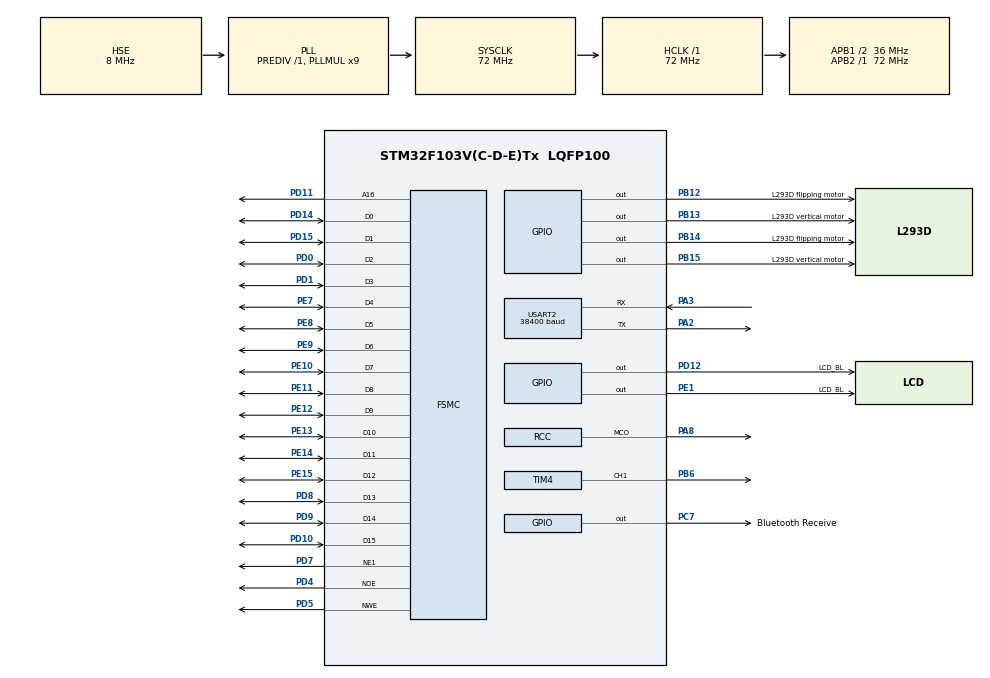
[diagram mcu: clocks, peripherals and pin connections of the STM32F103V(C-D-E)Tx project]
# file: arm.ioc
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Mcu.Family=STM32F1
Mcu.Name=STM32F103V(C-D-E)Tx
Mcu.Package=LQFP100
NVIC.PriorityGroup=NVIC_PRIORITYGROUP_4
NVIC.USART2_IRQn=true\:0\:0\:false\:false\:true\:true\:true
OSC_IN.Mode=HSE-External-Oscillator
OSC_IN.Signal=RCC_OSC_IN
OSC_OUT.Mode=HSE-External-Oscillator
OSC_OUT.Signal=RCC_OSC_OUT
PA13.Mode=Serial_Wire
PA13.Signal=SYS_JTMS-SWDIO
PA14.Mode=Serial_Wire
PA14.Signal=SYS_JTCK-SWCLK
PA2.Mode=Asynchronous
PA2.Signal=USART2_TX
PA3.Mode=Asynchronous
PA3.Signal=USART2_RX
PA8.Mode=Clock-out
PA8.Signal=RCC_MCO
PB12.GPIO_Label=L293D flipping motor
PB12.GPIO_Speed=GPIO_SPEED_FREQ_HIGH
PB12.Signal=GPIO_Output
PB13.GPIO_Label=L293D vertical motor
PB13.GPIO_Speed=GPIO_SPEED_FREQ_HIGH
PB13.Signal=GPIO_Output
PB14.GPIO_Label=L293D flipping motor
PB14.GPIO_Speed=GPIO_SPEED_FREQ_HIGH
PB14.Signal=GPIO_Output
PB15.GPIO_Label=L293D vertical motor
PB15.GPIO_Speed=GPIO_SPEED_FREQ_HIGH
PB15.Signal=GPIO_Output
PB6.Signal=S_TIM4_CH1
PC14-OSC32_IN.Mode=LSE-External-Oscillator
PC14-OSC32_IN.Signal=RCC_OSC32_IN
PC15-OSC32_OUT.Mode=LSE-External-Oscillator
PC15-OSC32_OUT.Signal=RCC_OSC32_OUT
PC7.GPIO_Label=Bluetooth Receive
PC7.Signal=GPIO_Output
PD0.Mode=16b-d1
PD0.Signal=FSMC_D2
PD1.Mode=16b-d1
PD1.Signal=FSMC_D3
PD10.Mode=16b-d1
PD10.Signal=FSMC_D15
PD11.Mode=A16_1
PD11.Signal=FSMC_A16
PD12.GPIO_Label=LCD_BL
PD12.GPIO_Speed=GPIO_SPEED_FREQ_HIGH
PD12.Signal=GPIO_Output
PD14.Mode=16b-d1
PD14.Signal=FSMC_D0
PD15.Mode=16b-d1
PD15.Signal=FSMC_D1
PD4.Mode=Lcd1
PD4.Signal=FSMC_NOE
PD5.Mode=Lcd1
PD5.Signal=FSMC_NWE
PD7.Mode=NorPsramChipSelect1_1
PD7.Signal=FSMC_NE1
PD8.Mode=16b-d1
PD8.Signal=FSMC_D13
PD9.Mode=16b-d1
PD9.Signal=FSMC_D14
PE1.GPIO_Label=LCD_BL
PE1.GPIO_Speed=GPIO_SPEED_FREQ_HIGH
PE1.Signal=GPIO_Output
PE10.Mode=16b-d1
PE10.Signal=FSMC_D7
PE11.Mode=16b-d1
PE11.Signal=FSMC_D8
PE12.Mode=16b-d1
PE12.Signal=FSMC_D9
PE13.Mode=16b-d1
PE13.Signal=FSMC_D10
PE14.Mode=16b-d1
PE14.Signal=FSMC_D11
PE15.Mode=16b-d1
PE15.Signal=FSMC_D12
PE7.Mode=16b-d1
PE7.Signal=FSMC_D4
PE8.Mode=16b-d1
PE8.Signal=FSMC_D5
PE9.Mode=16b-d1
PE9.Signal=FSMC_D6
ProjectManager.HeapSize=0x200
ProjectManager.StackSize=0x400
ProjectManager.TargetToolchain=MDK-ARM V5
RCC.AHBFreq_Value=72000000
RCC.APB1CLKDivider=RCC_HCLK_DIV2
RCC.APB1Freq_Value=36000000
RCC.APB1TimFreq_Value=72000000
RCC.APB2Freq_Value=72000000
RCC.APB2TimFreq_Value=72000000
RCC.HCLKFreq_Value=72000000
RCC.PLLMUL=RCC_PLL_MUL9
RCC.PLLSourceVirtual=RCC_PLLSOURCE_HSE
RCC.RCC_MCOSource=RCC_MCO1SOURCE_PLLCLK
RCC.SYSCLKFreq_VALUE=72000000
RCC.SYSCLKSource=RCC_SYSCLKSOURCE_PLLCLK
RCC.USBFreq_Value=72000000
SH.S_TIM4_CH1.0=TIM4_CH1,PWM Generation1 CH1
TIM4.Channel-PWM\ Generation1\ CH1=TIM_CHANNEL_1
TIM4.Period=1999
TIM4.Prescaler=719
USART2.BaudRate=38400
USART2.VirtualMode=VM_ASYNC
VP_TIM4_VS_ClockSourceINT.Mode=Internal
board=custom

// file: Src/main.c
/* USER CODE BEGIN Header */
/**
  ******************************************************************************
  * @file           : main.c
  * @brief          : Main program body
  ******************************************************************************
  * @attention
  *
  * <h2><center>&copy; Copyright (c) 2021 STMicroelectronics.
  * All rights reserved.</center></h2>
  *
  * This software component is licensed by ST under BSD 3-Clause license,
  * the "License"; You may not use this file except in compliance with the
  * License. You may obtain a copy of the License at:
  *                        opensource.org/licenses/BSD-3-Clause
  *
  ******************************************************************************
  */
/* USER CODE END Header */

#include "main.h"

/* USER CODE BEGIN Includes */
#include "lcd.h"

/* USER CODE END Includes */

/* USER CODE BEGIN PD */
#define BUFFER_LEN 1
#define LINE_SPACING 20

#define RIGHT_PULSE 35
#define LEFT_PULSE 215
#define MAGNET_PIN GPIO_PIN_12
#define MOTOR_PIN_1 GPIO_PIN_15
#define MOTOR_PIN_2 GPIO_PIN_13
/* USER CODE END PD */

TIM_HandleTypeDef htim4;

UART_HandleTypeDef huart2;

SRAM_HandleTypeDef hsram1;

/* USER CODE BEGIN PV */
uint8_t RX_BUFFER[BUFFER_LEN] = {0};
uint8_t TX_BUFFER[BUFFER_LEN] = {0};
int page = 1;
/* USER CODE END PV */

void SystemClock_Config(void);
static void MX_GPIO_Init(void);
static void MX_FSMC_Init(void);
static void MX_USART2_UART_Init(void);
static void MX_TIM4_Init(void);

/* USER CODE BEGIN 0 */
void turn_page(int next)
{
  LCD_Clear(0, 0, 240, 320, 0xFFFF);
  LCD_DrawString(70, LINE_SPACING * 7, "Turning");

  if (!next) {
    __HAL_TIM_SET_COMPARE(&htim4, TIM_CHANNEL_1, LEFT_PULSE);
    HAL_Delay(1000);
  }
  // start moving down
  HAL_GPIO_WritePin(GPIOB, MOTOR_PIN_1, GPIO_PIN_SET);

  page = page + (next ? 1 : -1);
  for (int i = 0; i < 5; i++)
  {
    if (i == 1)
    {
      // stop moving down
      HAL_GPIO_WritePin(GPIOB, MOTOR_PIN_2, GPIO_PIN_SET);
      // magnet on
      HAL_GPIO_WritePin(GPIOB, MAGNET_PIN, GPIO_PIN_SET);
      // start flipping next page
      __HAL_TIM_SET_COMPARE(&htim4, TIM_CHANNEL_1, (next ? LEFT_PULSE : RIGHT_PULSE));
    }
    else if (i == 4)
    {
      // magnet off
      HAL_GPIO_WritePin(GPIOB, MAGNET_PIN, GPIO_PIN_RESET);
      // start moving up
      HAL_GPIO_WritePin(GPIOB, MOTOR_PIN_1, GPIO_PIN_RESET);
    }

    LCD_DrawString(130 + i * 5, LINE_SPACING * 7, ".");
    HAL_Delay(500);
  }
  LCD_Clear(0, 0, 240, 320, 0xFFFF);

  // stop moving up
  HAL_GPIO_WritePin(GPIOB, MOTOR_PIN_2, GPIO_PIN_RESET);
  __HAL_TIM_SET_COMPARE(&htim4, TIM_CHANNEL_1, RIGHT_PULSE);
  HAL_Delay(500);
}
/* USER CODE END 0 */

int main(void)
{

  /* MCU Configuration--------------------------------------------------------*/

  /* Reset of all peripherals, Initializes the Flash interface and the Systick. */
  HAL_Init();

  /* Configure the system clock */
  SystemClock_Config();

  /* Initialize all configured peripherals */
  MX_GPIO_Init();
  MX_FSMC_Init();
  MX_USART2_UART_Init();
  MX_TIM4_Init();
  /* USER CODE BEGIN 2 */
	LCD_INIT();

	// for magnet
	HAL_GPIO_WritePin(GPIOB, MAGNET_PIN, GPIO_PIN_RESET);

  // for flipping motor
	__HAL_TIM_SET_COMPARE(&htim4, TIM_CHANNEL_1, RIGHT_PULSE);

	// for vertical motor
	HAL_GPIO_WritePin(GPIOB, MOTOR_PIN_1, GPIO_PIN_RESET);
	HAL_GPIO_WritePin(GPIOB, MOTOR_PIN_2, GPIO_PIN_RESET);

	// variables
	char pageStr[2];

	HAL_UART_Receive_IT(&huart2, RX_BUFFER, BUFFER_LEN);
  /* USER CODE END 2 */

  /* Infinite loop */
  while (1)
  {

    /* USER CODE BEGIN 3 */
		HAL_UART_Receive_IT(&huart2, RX_BUFFER, BUFFER_LEN);
    // received signal or k2 pressed
		if(RX_BUFFER[0] == '1' || HAL_GPIO_ReadPin(GPIOC, GPIO_PIN_13) == GPIO_PIN_SET)
    {
			turn_page(1);
		}
    else if ((RX_BUFFER[0] == '2' || HAL_GPIO_ReadPin(GPIOA, GPIO_PIN_0) == GPIO_PIN_SET) && page > 1) {
      turn_page(0);
    }
		else {
			sprintf(pageStr, "%d", page);
			LCD_DrawString(100, LINE_SPACING * 5, "Ready");
			LCD_DrawString(95, LINE_SPACING * 7, "Page");
			LCD_DrawString(130, LINE_SPACING * 7, pageStr);
		}
  }
  /* USER CODE END 3 */
}

void SystemClock_Config(void)
{
  RCC_OscInitTypeDef RCC_OscInitStruct = {0};
  RCC_ClkInitTypeDef RCC_ClkInitStruct = {0};

  /** Initializes the CPU, AHB and APB busses clocks
  */
  RCC_OscInitStruct.OscillatorType = RCC_OSCILLATORTYPE_HSE;
  RCC_OscInitStruct.HSEState = RCC_HSE_ON;
  RCC_OscInitStruct.HSEPredivValue = RCC_HSE_PREDIV_DIV1;
  RCC_OscInitStruct.HSIState = RCC_HSI_ON;
  RCC_OscInitStruct.PLL.PLLState = RCC_PLL_ON;
  RCC_OscInitStruct.PLL.PLLSource = RCC_PLLSOURCE_HSE;
  RCC_OscInitStruct.PLL.PLLMUL = RCC_PLL_MUL9;
  if (HAL_RCC_OscConfig(&RCC_OscInitStruct) != HAL_OK)
  {
    Error_Handler();
  }
  /** Initializes the CPU, AHB and APB busses clocks
  */
  RCC_ClkInitStruct.ClockType = RCC_CLOCKTYPE_HCLK|RCC_CLOCKTYPE_SYSCLK
                              |RCC_CLOCKTYPE_PCLK1|RCC_CLOCKTYPE_PCLK2;
  RCC_ClkInitStruct.SYSCLKSource = RCC_SYSCLKSOURCE_PLLCLK;
  RCC_ClkInitStruct.AHBCLKDivider = RCC_SYSCLK_DIV1;
  RCC_ClkInitStruct.APB1CLKDivider = RCC_HCLK_DIV2;
  RCC_ClkInitStruct.APB2CLKDivider = RCC_HCLK_DIV1;

  if (HAL_RCC_ClockConfig(&RCC_ClkInitStruct, FLASH_LATENCY_2) != HAL_OK)
  {
    Error_Handler();
  }
  HAL_RCC_MCOConfig(RCC_MCO, RCC_MCO1SOURCE_PLLCLK, RCC_MCODIV_1);
}

static void MX_TIM4_Init(void)
{

  TIM_ClockConfigTypeDef sClockSourceConfig = {0};
  TIM_MasterConfigTypeDef sMasterConfig = {0};
  TIM_OC_InitTypeDef sConfigOC = {0};

  htim4.Instance = TIM4;
  htim4.Init.Prescaler = 719;
  htim4.Init.CounterMode = TIM_COUNTERMODE_UP;
  htim4.Init.Period = 1999;
  htim4.Init.ClockDivision = TIM_CLOCKDIVISION_DIV1;
  htim4.Init.AutoReloadPreload = TIM_AUTORELOAD_PRELOAD_DISABLE;
  if (HAL_TIM_Base_Init(&htim4) != HAL_OK)
  {
    Error_Handler();
  }
  sClockSourceConfig.ClockSource = TIM_CLOCKSOURCE_INTERNAL;
  if (HAL_TIM_ConfigClockSource(&htim4, &sClockSourceConfig) != HAL_OK)
  {
    Error_Handler();
  }
  if (HAL_TIM_PWM_Init(&htim4) != HAL_OK)
  {
    Error_Handler();
  }
  sMasterConfig.MasterOutputTrigger = TIM_TRGO_RESET;
  sMasterConfig.MasterSlaveMode = TIM_MASTERSLAVEMODE_DISABLE;
  if (HAL_TIMEx_MasterConfigSynchronization(&htim4, &sMasterConfig) != HAL_OK)
  {
    Error_Handler();
  }
  sConfigOC.OCMode = TIM_OCMODE_PWM1;
  sConfigOC.Pulse = 0;
  sConfigOC.OCPolarity = TIM_OCPOLARITY_HIGH;
  sConfigOC.OCFastMode = TIM_OCFAST_DISABLE;
  if (HAL_TIM_PWM_ConfigChannel(&htim4, &sConfigOC, TIM_CHANNEL_1) != HAL_OK)
  {
    Error_Handler();
  }
  /* USER CODE BEGIN TIM4_Init 2 */
	HAL_TIM_PWM_Start(&htim4, TIM_CHANNEL_1);
  /* USER CODE END TIM4_Init 2 */
  HAL_TIM_MspPostInit(&htim4);

}

static void MX_USART2_UART_Init(void)
{

  huart2.Instance = USART2;
  huart2.Init.BaudRate = 38400;
  huart2.Init.WordLength = UART_WORDLENGTH_8B;
  huart2.Init.StopBits = UART_STOPBITS_1;
  huart2.Init.Parity = UART_PARITY_NONE;
  huart2.Init.Mode = UART_MODE_TX_RX;
  huart2.Init.HwFlowCtl = UART_HWCONTROL_NONE;
  huart2.Init.OverSampling = UART_OVERSAMPLING_16;
  if (HAL_UART_Init(&huart2) != HAL_OK)
  {
    Error_Handler();
  }

}

static void MX_GPIO_Init(void)
{
  GPIO_InitTypeDef GPIO_InitStruct = {0};

  /* GPIO Ports Clock Enable */
  __HAL_RCC_GPIOC_CLK_ENABLE();
  __HAL_RCC_GPIOA_CLK_ENABLE();
  __HAL_RCC_GPIOE_CLK_ENABLE();
  __HAL_RCC_GPIOB_CLK_ENABLE();
  __HAL_RCC_GPIOD_CLK_ENABLE();

  /*Configure GPIO pin Output Level */
  HAL_GPIO_WritePin(GPIOB, electromagnet_Pin|L293D_vertical_motor_Pin|nothing_Pin|L293D_vertical_motorB15_Pin, GPIO_PIN_RESET);

  /*Configure GPIO pin Output Level */
  HAL_GPIO_WritePin(LCD_BL_GPIO_Port, LCD_BL_Pin, GPIO_PIN_RESET);

  /*Configure GPIO pin Output Level */
  HAL_GPIO_WritePin(LCD_BLE1_GPIO_Port, LCD_BLE1_Pin, GPIO_PIN_RESET);

  /*Configure GPIO pins : electromagnet_Pin L293D_vertical_motor_Pin nothing_Pin L293D_vertical_motorB15_Pin */
  GPIO_InitStruct.Pin = electromagnet_Pin|L293D_vertical_motor_Pin|nothing_Pin|L293D_vertical_motorB15_Pin;
  GPIO_InitStruct.Mode = GPIO_MODE_OUTPUT_PP;
  GPIO_InitStruct.Pull = GPIO_NOPULL;
  GPIO_InitStruct.Speed = GPIO_SPEED_FREQ_HIGH;
  HAL_GPIO_Init(GPIOB, &GPIO_InitStruct);

  /*Configure GPIO pin : LCD_BL_Pin */
  GPIO_InitStruct.Pin = LCD_BL_Pin;
  GPIO_InitStruct.Mode = GPIO_MODE_OUTPUT_PP;
  GPIO_InitStruct.Pull = GPIO_NOPULL;
  GPIO_InitStruct.Speed = GPIO_SPEED_FREQ_HIGH;
  HAL_GPIO_Init(LCD_BL_GPIO_Port, &GPIO_InitStruct);

  /*Configure GPIO pin : PA8 */
  GPIO_InitStruct.Pin = GPIO_PIN_8;
  GPIO_InitStruct.Mode = GPIO_MODE_AF_PP;
  GPIO_InitStruct.Speed = GPIO_SPEED_FREQ_LOW;
  HAL_GPIO_Init(GPIOA, &GPIO_InitStruct);

  /*Configure GPIO pin : LCD_BLE1_Pin */
  GPIO_InitStruct.Pin = LCD_BLE1_Pin;
  GPIO_InitStruct.Mode = GPIO_MODE_OUTPUT_PP;
  GPIO_InitStruct.Pull = GPIO_NOPULL;
  GPIO_InitStruct.Speed = GPIO_SPEED_FREQ_HIGH;
  HAL_GPIO_Init(LCD_BLE1_GPIO_Port, &GPIO_InitStruct);

}

/* FSMC initialization function */
static void MX_FSMC_Init(void)
{

  FSMC_NORSRAM_TimingTypeDef Timing = {0};

  /** Perform the SRAM1 memory initialization sequence
  */
  hsram1.Instance = FSMC_NORSRAM_DEVICE;
  hsram1.Extended = FSMC_NORSRAM_EXTENDED_DEVICE;
  /* hsram1.Init */
  hsram1.Init.NSBank = FSMC_NORSRAM_BANK1;
  hsram1.Init.DataAddressMux = FSMC_DATA_ADDRESS_MUX_DISABLE;
  hsram1.Init.MemoryType = FSMC_MEMORY_TYPE_SRAM;
  hsram1.Init.MemoryDataWidth = FSMC_NORSRAM_MEM_BUS_WIDTH_16;
  hsram1.Init.BurstAccessMode = FSMC_BURST_ACCESS_MODE_DISABLE;
  hsram1.Init.WaitSignalPolarity = FSMC_WAIT_SIGNAL_POLARITY_LOW;
  hsram1.Init.WrapMode = FSMC_WRAP_MODE_DISABLE;
  hsram1.Init.WaitSignalActive = FSMC_WAIT_TIMING_BEFORE_WS;
  hsram1.Init.WriteOperation = FSMC_WRITE_OPERATION_ENABLE;
  hsram1.Init.WaitSignal = FSMC_WAIT_SIGNAL_DISABLE;
  hsram1.Init.ExtendedMode = FSMC_EXTENDED_MODE_DISABLE;
  hsram1.Init.AsynchronousWait = FSMC_ASYNCHRONOUS_WAIT_DISABLE;
  hsram1.Init.WriteBurst = FSMC_WRITE_BURST_DISABLE;
  /* Timing */
  Timing.AddressSetupTime = 15;
  Timing.AddressHoldTime = 15;
  Timing.DataSetupTime = 255;
  Timing.BusTurnAroundDuration = 15;
  Timing.CLKDivision = 16;
  Timing.DataLatency = 17;
  Timing.AccessMode = FSMC_ACCESS_MODE_A;
  /* ExtTiming */

  if (HAL_SRAM_Init(&hsram1, &Timing, NULL) != HAL_OK)
  {
    Error_Handler( );
  }

  /** Disconnect NADV
  */

  __HAL_AFIO_FSMCNADV_DISCONNECTED();

}

/* USER CODE BEGIN 4 */
void HAL_UART_RxCpltCallback(UART_HandleTypeDef *huart)
{
    if(huart->Instance == huart2.Instance)
    {
    HAL_UART_Receive_IT(&huart2, RX_BUFFER, BUFFER_LEN);
    }
}
/* USER CODE END 4 */

void Error_Handler(void)
{
}

/************************ (C) COPYRIGHT STMicroelectronics *****END OF FILE****/
